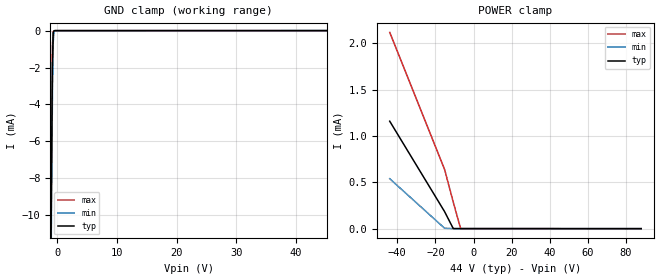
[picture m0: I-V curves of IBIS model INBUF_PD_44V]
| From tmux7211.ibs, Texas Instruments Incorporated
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| Model6
[Model]   INBUF_PD_44V
Model_type   Input
Vinl = 0.8
Vinh = 1.3
|   typ   min   max
C_comp   1.85pF   1.7pF   2.1pF
[Voltage Range]   44   39.6   48.4
[Temperature Range]   27   130   -40
[Power Clamp Reference]   44   44   44
[GND Clamp Reference]   0   0   0
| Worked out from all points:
|   GND clamp passes 1 mA (typ) near -0.78 V on its own axis
[GND Clamp]
|   Voltage   I(typ)   I(min)   I(max)
-44V      -2.328A    -2.326A    -2.332A
-1.1V     -12.66mA   -14.24mA   -11.59mA
-968mV    -6.594mA   -8.321mA   -5.409mA
-836mV    -1.77mA    -3.378mA   -813.6uA
-704mV    -86.03uA   -612uA     -49.19uA
-572mV    -14.17uA   -32.03uA   -21.99uA
-440mV    -2.586uA   -3.661uA   -4.159uA
88V       0A         0A         0A
[POWER Clamp]
|   Voltage   I(typ)   I(min)   I(max)
-44V      1.16mA     539.3uA    2.119mA
-15.22V   184.6uA    4.744uA    640.7uA
-11V      14.89uA    444.3nA    314.4uA
-10.6V    2.402uA    445.3nA    283.5uA
-10.34V   492.9nA    446nA      262.9uA
-6.776V   503.1nA    452.2nA    913.1nA
-6.644V   503.5nA    452.4nA    616.3nA
36.26V    508.7nA    437.4nA    641.5nA
40.74V    494.7nA    0A         637.9nA
44.44V    0A         0A         630.7nA
48.14V    0A         0A         0A
88V       0A         0A         0A
